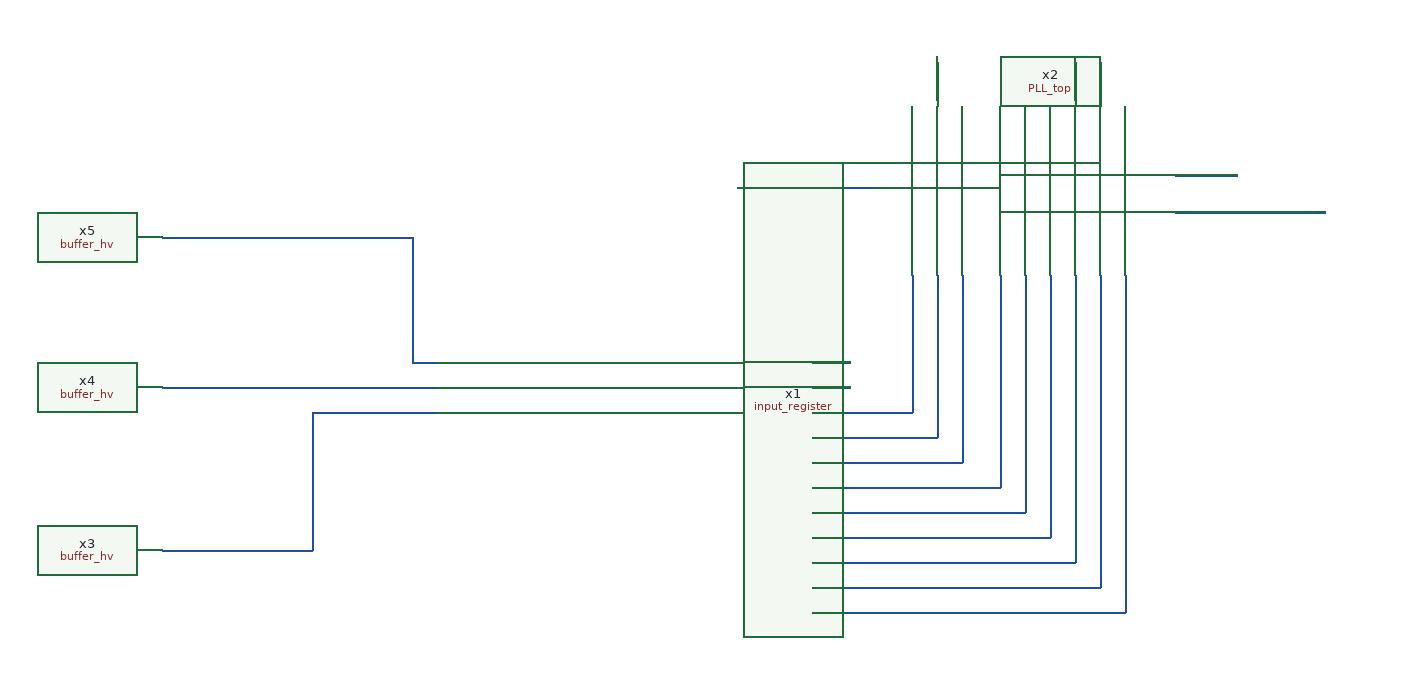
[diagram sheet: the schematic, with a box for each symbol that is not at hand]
v {xschem version=3.4.8RC file_version=1.3}
G {}
K {}
V {}
S {}
F {}
E {}
N 150 -10 200 -10 {lab=#net1}
N -170 -20 -90 -20 {lab=#net2}
N -200 0 -90 -0 {lab=#net3}
N 150 20 270 20 {lab=#net4}
N 90 -100 90 -70 {lab=#net5}
N 70 -100 70 -70 {lab=#net6}
N -40 -100 -40 -70 {lab=#net7}
N -140 180 -60 180 {lab=#net8}
N -60 70 -60 180 {lab=#net8}
N -140 200 -40 200 {lab=#net9}
N -40 70 -40 200 {lab=#net9}
N -140 220 -20 220 {lab=#net10}
N -20 70 -20 220 {lab=#net10}
N 10 70 10 240 {lab=#net11}
N -140 240 10 240 {lab=#net11}
N -140 260 30 260 {lab=#net12}
N 30 70 30 260 {lab=#net12}
N -140 280 50 280 {lab=#net13}
N 50 70 50 280 {lab=#net13}
N 70 70 70 300 {lab=#net14}
N -140 300 70 300 {lab=#net14}
N -140 320 90 320 {lab=#net15}
N 90 70 90 320 {lab=#net15}
N -140 340 110 340 {lab=#net16}
N 110 70 110 340 {lab=#net16}
N -140 140 -110 140 {lab=#net17}
N -140 160 -110 160 {lab=#net18}
N -540 180 -440 180 {lab=#net19}
N -660 290 -540 290 {lab=#net19}
N -540 180 -540 290 {lab=#net19}
N -660 160 -440 160 {lab=#net20}
N -660 40 -460 40 {lab=#net21}
N -460 40 -460 140 {lab=#net21}
N -460 140 -440 140 {lab=#net21}
C {/foss/designs/CHIP-PLL/schematics/top/PLL_top.sym} 60 -80 0 0 {name=x2}
C {/foss/designs/CHIP-PLL/schematics/divider/schematics/input_register.sym} -290 240 0 0 {name=x1}
C {/foss/designs/CHIP-PLL/schematics/misc/buffer_hv.sym} -630 290 0 0 {name=x3}
C {/foss/designs/CHIP-PLL/schematics/misc/buffer_hv.sym} -630 160 0 0 {name=x4}
C {/foss/designs/CHIP-PLL/schematics/misc/buffer_hv.sym} -630 40 0 0 {name=x5}
